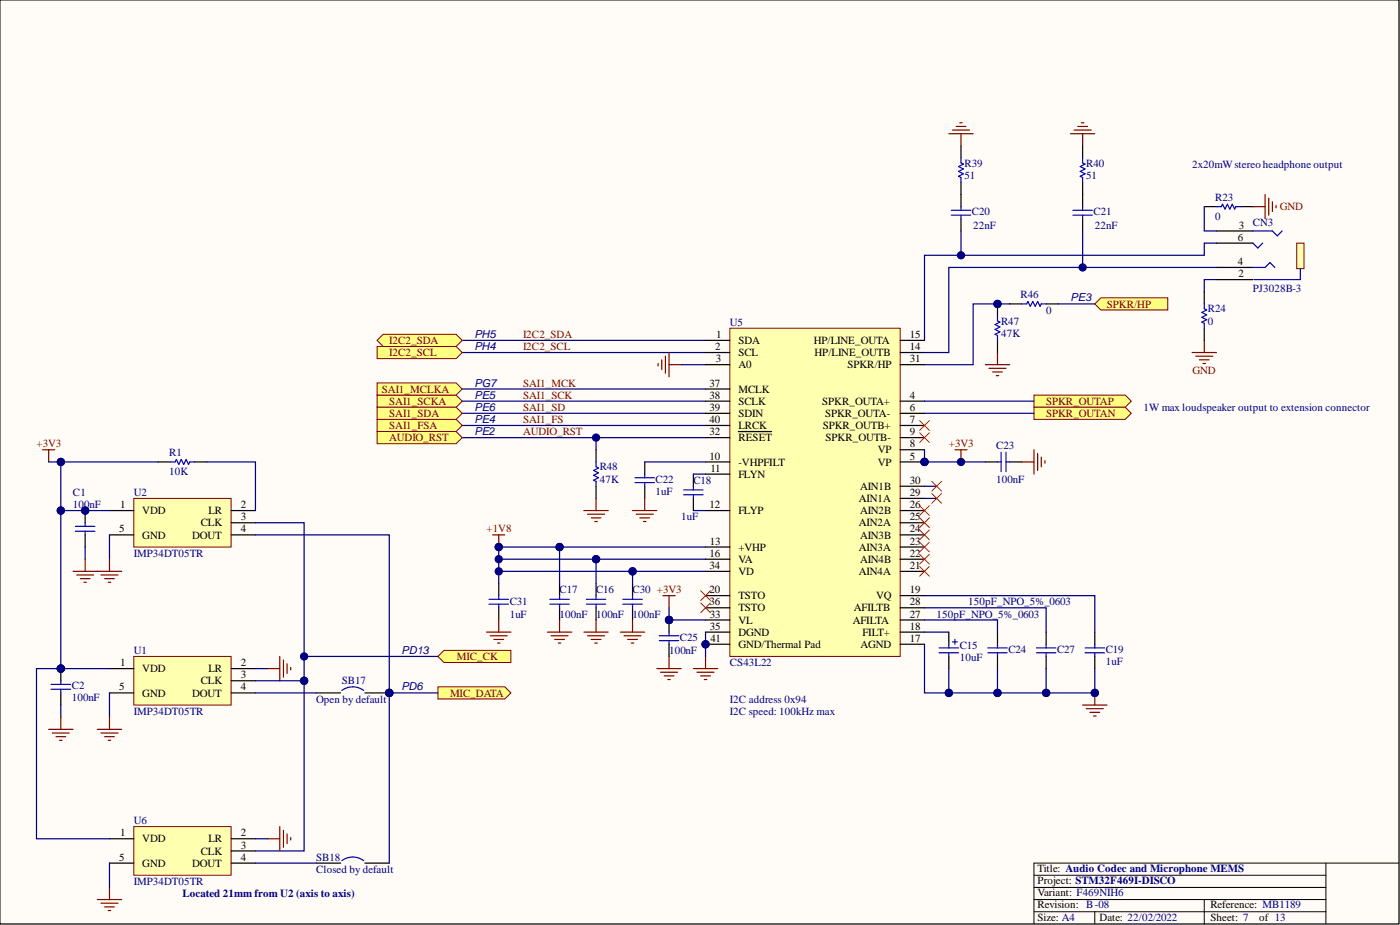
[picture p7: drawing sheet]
<svg xmlns="http://www.w3.org/2000/svg" width="292mm" height="193mm" viewBox="0 0 292 193" stroke-linecap="round" stroke-linejoin="round" font-family="sans-serif">
<defs><g id="words">
<g font-size="2.3" fill="#000080">
<text x="201.3" y="34.7">R39</text>
<text x="226.6" y="34.7">R40</text>
<text x="248.7" y="35">2x20mWstereo headphone output</text>
<text x="201.3" y="37.3">51</text>
<text x="226.6" y="37.3">51</text>
<text x="253.5" y="41.8">R23</text>
<text x="202.8" y="44.9">C20</text>
<text x="203" y="47.7">22nF</text>
<text x="228.2" y="44.9">C21</text>
<text x="228.4" y="47.7">22nF</text>
<text x="253.5" y="45.9">0</text>
<text x="261.4" y="47.2">CN3</text>
<text x="212.9" y="62.1">R46</text>
<text x="218.3" y="65.4">0</text>
<text x="223.3" y="62.9">PE3</text>
<text x="252" y="65.2">R24</text>
<text x="261.4" y="60.9">PJ3028B-3</text>
<text x="99" y="70.5">PH5</text>
<text x="152.3" y="68">U5</text>
<text x="208.9" y="67.7">R47</text>
<text x="208.9" y="70.2">47K</text>
<text x="252" y="67.7">0</text>
<text x="99" y="73">PH4</text>
<text x="99" y="83.2">PE5</text>
<text x="99" y="80.6">PG7</text>
<text x="99" y="85.7">PE6</text>
<text x="99" y="88.3">PE4</text>
<text x="238.6" y="85.7">1W max loudspeaker output to extension connector</text>
<text x="35.3" y="95.1">R1</text>
<text x="99" y="90.8">PE2</text>
<text x="207.9" y="93.6">C23</text>
<text x="35.3" y="99.2">10K</text>
<text x="125.1" y="98.1">R48</text>
<text x="125.1" y="100.7">47K</text>
<text x="136.8" y="100.7">C22</text>
<text x="144.7" y="100.9">C18</text>
<text x="207.9" y="100.7">100nF</text>
<text x="15.2" y="103.5">C1</text>
<text x="15.2" y="106">100nF</text>
<text x="27.9" y="103.5">U2</text>
<text x="136.8" y="103.2">1uF</text>
<text x="142.1" y="108.5">1uF</text>
<text x="27.9" y="116.1">IMP34DT05TR</text>
<text x="116.7" y="123.8">C17</text>
<text x="124.4" y="123.8">C16</text>
<text x="132" y="123.8">C30 +3V3</text>
<text x="106.3" y="126.3">C31</text>
<text x="106.3" y="128.8">1uF</text>
<text x="116.7" y="128.8">100nF</text>
<text x="124.4" y="128.8">100nF</text>
<text x="132" y="128.8">100nF</text>
<text x="195.4" y="128.8">150pF_NPO_5%_0603</text>
<text x="202" y="126.3">150pF_NPO_5%_0603</text>
<text x="27.9" y="136.4">U1</text>
<text x="83.8" y="136.4">PD13</text>
<text x="139.6" y="136.4">100nF</text>
<text x="141.9" y="133.6">C25</text>
<text x="200.2" y="135.4">C15</text>
<text x="200.2" y="138">10uF</text>
<text x="210.4" y="136.2">C24</text>
<text x="220.6" y="136.2">C27</text>
<text x="230.7" y="136.2">C19</text>
<text x="15" y="143.8">C2</text>
<text x="71.3" y="142.8">SB17</text>
<text x="152.3" y="139">CS43L22</text>
<text x="230.7" y="138.7">1uF</text>
<text x="15" y="146.3">100nF</text>
<text x="27.9" y="149.1">IMP34DT05TR</text>
<text x="66" y="146.6">Open by default</text>
<text x="83.8" y="144">PD6</text>
<text x="152.3" y="146.6">I2C address 0x94</text>
<text x="152.3" y="149.1">I2C speed: 100kHz max</text>
<text x="27.9" y="171.9">U6</text>
<text x="66" y="179.5">SB18</text>
<text x="27.9" y="184.6">IMP34DT05TR</text>
<text x="66" y="182.1">Closed by default</text>
<text x="38.1" y="187.2">Located 21mm from U2 (axis to axis)</text>
</g>
<g font-size="2.3">
<text x="258.5" y="47.7">3</text>
<text x="258.3" y="50.2">6</text>
<text x="258.3" y="55.3">4</text>
<text x="258.4" y="57.8">2</text>
<text x="149.4" y="70.5">1</text>
<text x="154.1" y="71.8">SDA</text>
<text x="169.8" y="71.8">HP/LINE_OUTA</text>
<text x="189.8" y="70.5">15</text>
<text x="149.2" y="73">2</text>
<text x="149.3" y="75.6">3</text>
<text x="154.1" y="74.3">SCL</text>
<text x="154.1" y="76.8">A0</text>
<text x="170" y="74.3">HP/LINE_OUTB</text>
<text x="176.8" y="76.8">SPKR/HP</text>
<text x="189.8" y="73">14</text>
<text x="189.8" y="75.6">31</text>
<text x="148.1" y="80.6">37</text>
<text x="148.1" y="83.2">38</text>
<text x="154.1" y="81.9">MCLK</text>
<text x="189.8" y="83.2">4</text>
<text x="148.1" y="85.7">39</text>
<text x="148.1" y="88.3">40</text>
<text x="154.1" y="84.4">SCLK</text>
<text x="154.1" y="87">SDIN</text>
<text x="154.1" y="89.5">LRCK</text>
<text x="171.6" y="84.4">SPKR_OUTA+</text>
<text x="171.7" y="89.5">SPKR_OUTB+</text>
<text x="172.2" y="87">SPKR_OUTA-</text>
<text x="189.8" y="85.7">6</text>
<text x="189.8" y="88.3">7</text>
<text x="148.1" y="95.9">10</text>
<text x="148.1" y="90.8">32</text>
<text x="154.1" y="92.1">RESET</text>
<text x="172.2" y="92.1">SPKR_OUTB-</text>
<text x="183.2" y="94.6">VP</text>
<text x="189.8" y="95.9">5</text>
<text x="189.8" y="93.3">8</text>
<text x="189.8" y="90.8">9</text>
<text x="148.2" y="98.4">11</text>
<text x="154.1" y="97.1">-VHPFILT</text>
<text x="154.1" y="99.7">FLYN</text>
<text x="183.2" y="97.1">VP</text>
<text x="189.8" y="100.9">30</text>
<text x="25" y="106">1</text>
<text x="29.7" y="107.3">VDD</text>
<text x="43.5" y="107.3">LR</text>
<text x="50.3" y="106">2</text>
<text x="148.1" y="106">12</text>
<text x="154.1" y="107.3">FLYP</text>
<text x="179.2" y="104.7">AIN1A</text>
<text x="179.4" y="107.3">AIN2B</text>
<text x="179.4" y="102.2">AIN1B</text>
<text x="189.8" y="106">26</text>
<text x="189.8" y="103.5">29</text>
<text x="24.9" y="111.1">5</text>
<text x="29.7" y="112.3">GND</text>
<text x="40.1" y="112.3">DOUT</text>
<text x="41.9" y="109.8">CLK</text>
<text x="50.3" y="111.1">4</text>
<text x="50.3" y="108.5">3</text>
<text x="148.1" y="113.6">13</text>
<text x="179.2" y="109.8">AIN2A</text>
<text x="179.4" y="112.3">AIN3B</text>
<text x="189.8" y="113.6">23</text>
<text x="189.8" y="111.1">24</text>
<text x="189.8" y="108.5">25</text>
<text x="148.1" y="116.1">16</text>
<text x="148.1" y="118.7">34</text>
<text x="154.1" y="114.9">+VHP</text>
<text x="154.1" y="117.4">VA</text>
<text x="154.1" y="120">VD</text>
<text x="179.2" y="120">AIN4A</text>
<text x="179.2" y="114.9">AIN3A</text>
<text x="179.4" y="117.4">AIN4B</text>
<text x="189.8" y="118.7">21</text>
<text x="189.8" y="116.1">22</text>
<text x="148.1" y="123.8">20</text>
<text x="154.1" y="125">TSTO</text>
<text x="182.8" y="125">VQ</text>
<text x="189.8" y="123.8">19</text>
<text x="148.1" y="126.3">36</text>
<text x="148.1" y="128.8">33</text>
<text x="148.1" y="131.4">35</text>
<text x="154.1" y="130.1">VL</text>
<text x="154.1" y="127.6">TSTO</text>
<text x="177.9" y="130.1">AFILTA</text>
<text x="178.2" y="127.6">AFILTB</text>
<text x="189.8" y="131.4">18</text>
<text x="189.8" y="128.8">27</text>
<text x="189.8" y="126.3">28</text>
<text x="148.2" y="133.9">41</text>
<text x="154.1" y="132.6">DGND</text>
<text x="154.1" y="135.2">GND/Thermal Pad</text>
<text x="179.5" y="135.2">AGND</text>
<text x="179.9" y="132.6">FILT+</text>
<text x="189.8" y="133.9">17</text>
<text x="25" y="139">1</text>
<text x="29.7" y="140.2">VDD</text>
<text x="41.9" y="142.8">CLK</text>
<text x="43.5" y="140.2">LR</text>
<text x="50.3" y="141.5">3</text>
<text x="50.3" y="139">2</text>
<text x="24.9" y="144">5</text>
<text x="29.7" y="145.3">GND</text>
<text x="40.1" y="145.3">DOUT</text>
<text x="50.3" y="144">4</text>
<text x="24.9" y="179.5">5</text>
<text x="25" y="174.5">1</text>
<text x="29.7" y="175.7">VDD</text>
<text x="41.9" y="178.3">CLK</text>
<text x="43.5" y="175.7">LR</text>
<text x="50.3" y="179.5">4</text>
<text x="50.3" y="177">3</text>
<text x="50.3" y="174.5">2</text>
<text x="29.7" y="180.8">GND</text>
<text x="40.1" y="180.8">DOUT</text>
<text x="216.5" y="181.8">Title: Audio Codec and Microphone MEMS</text>
<text x="216.5" y="184.4">Project: STM32F469I-DISCO</text>
<text x="216.5" y="189.4">Revision: B-08</text>
<text x="216.5" y="186.9">Variant: F469NIH6</text>
<text x="252.5" y="189.4">Reference: MB1189</text>
<text x="216.5" y="192.2">Size: A4</text>
<text x="229.4" y="192.2">Date: 22/02/2022</text>
<text x="252.5" y="192.2">Sheet: 7</text>
<text x="262.7" y="192.2">of 13</text>
</g>
<g font-size="2.3" fill="#800000">
<text x="267" y="43.9">GND</text>
<text x="231" y="64.2">SPKR/HP</text>
<text x="81.2" y="71.8">I2C2_SDA</text>
<text x="109.1" y="70.5">I2C2_SDA</text>
<text x="81.2" y="74.3">I2C2_SCL</text>
<text x="109.1" y="73">I2C2_SCL</text>
<text x="79.7" y="81.9">SAI1_MCLKA</text>
<text x="109.1" y="80.6">SAI1_MCK</text>
<text x="109.1" y="83.2">SAI1_SCK</text>
<text x="248.8" y="78.1">GND</text>
<text x="81.2" y="84.4">SAI1_SCKA</text>
<text x="81.2" y="89.5">SAI1_FSA</text>
<text x="81.2" y="87">SAI1_SDA</text>
<text x="109.1" y="85.7">SAI1_SD</text>
<text x="109.1" y="88.3">SAI1_FS</text>
<text x="218.3" y="84.4">SPKR_OUTAP</text>
<text x="218.3" y="87">SPKR_OUTAN</text>
<text x="7.6" y="93.3">+3V3</text>
<text x="81.2" y="92.1">AUDIO_RST</text>
<text x="109.1" y="90.8">AUDIO_RST</text>
<text x="198" y="93.3">+3V3</text>
<text x="101.5" y="111.1">+1V8</text>
<text x="95.3" y="137.7">MIC_CK</text>
<text x="93.9" y="145.3">MIC_DATA</text>
</g>
</g></defs>
<path d="M0 0h291.9v192.7h-291.9z" fill-rule="evenodd" fill="#fffcf8"/>
<path d="M0 0h291.9v192.7h-291.9z" fill="none" stroke="#000" stroke-width=".21"/>
<path d="M0 0h291.9v192.7h-291.9z" fill-rule="evenodd" fill="#fffcf8"/>
<path d="M0 0h291.9v192.7h-291.9zM215.7 182.6h60.9M215.7 185.1h60.9M215.7 190.2h60.9M215.7 187.7h60.9M228.4 190.2v2.5M251.3 187.7v5M276.6 180.1v12.6M291.9 180.1h-76.2v12.6" fill="none" stroke="#000" stroke-width=".21"/>
<g fill="none" stroke="#800000" stroke-width=".25">
<path d="M198 27.9h5M198.7 27.1h3.6M199.5 26.4h2M200.2 25.6h.6M200.5 27.9v2.5M223.3 27.9h5.1M224.1 27.1h3.6M224.9 26.4h2M225.6 25.6h.5M225.9 27.9v2.5M121.8 106.5h5.1M122.6 107.3h3.5"/>
<path d="M123.3 108h2.1M124.1 108.8h.5M124.4 104v2.5M144.7 139.5h5M147.2 136.9v2.6M145.4 140.2h3.6M146.2 141h2M147 141.8h.5"/>
</g>
<path d="M225.9 48.2v7.6M96.4 73.5h50.8M96.4 71h50.8M96.4 83.7h50.8M96.4 86.2h50.8M96.4 88.8h50.8M96.4 81.2h50.8M147.2 131.9v5" fill="none" stroke="#000080" stroke-width=".25"/>
<circle cx="225.9" cy="55.8" r=".76" fill="#000080"/>
<circle cx="225.9" cy="55.8" r=".76" fill="none" stroke="#000080" stroke-width=".21"/>
<path d="M200.5 48.2v5.1" fill="none" stroke="#000080" stroke-width=".25"/>
<circle cx="200.5" cy="53.3" r=".76" fill="#000080"/>
<circle cx="200.5" cy="53.3" r=".76" fill="none" stroke="#000080" stroke-width=".21"/>
<path d="M137.3 75.8v.5M138.1 75.1v2M138.8 74.3v3.6M139.6 73.5v5.1M139.6 76.1h2.5" fill="none" stroke="#800000" stroke-width=".25"/>
<path d="M142.1 76.1h5.1M96.4 91.3h50.8" fill="none" stroke="#000080" stroke-width=".25"/>
<circle cx="192.9" cy="96.4" r=".76" fill="#000080"/>
<circle cx="192.9" cy="96.4" r=".76" fill="none" stroke="#000080" stroke-width=".21"/>
<circle cx="147.2" cy="134.4" r=".76" fill="#000080"/>
<circle cx="147.2" cy="134.4" r=".76" fill="none" stroke="#000080" stroke-width=".21"/>
<path d="M152.3 68.5h35.5v68.4h-35.5z" fill-rule="evenodd" fill="#ffffb0"/>
<path d="M152.3 68.5h35.5v68.4h-35.5z" fill="none" stroke="#800000" stroke-width=".21"/>
<path d="M147.2 71h5.1M147.2 73.5h5.1M147.2 76.1h5.1M187.8 83.7h5.1M187.8 96.4h5.1" fill="none" stroke="#000" stroke-width=".25"/>
<circle cx="192.9" cy="96.4" r=".76" fill="#000080"/>
<circle cx="192.9" cy="96.4" r=".76" fill="none" stroke="#000080" stroke-width=".21"/>
<g fill="none" stroke="#000" stroke-width=".25">
<path d="M187.8 73.5h5.1M187.8 71h5.1M187.8 76.1h5.1M147.2 86.2h5.1M147.2 88.8h5.1M147.2 91.3h5.1M147.2 96.4h5.1M147.2 98.9h5.1M147.2 81.2h5.1M147.2 83.7h5.1M154.1 90h6.9M187.8 86.2h5.1"/>
<path d="M187.8 88.8h5.1M187.8 93.8h5.1M187.8 91.3h5.1M147.2 106.5h5.1M147.2 114.1h5.1M147.2 116.7h5.1M147.2 119.2h5.1M187.8 106.5h5.1M187.8 114.1h5.1M187.8 116.7h5.1M187.8 119.2h5.1M187.8 111.6h5.1"/>
<path d="M187.8 109h5.1M187.8 104h5.1M187.8 101.4h5.1M147.2 134.4h5.1M147.2 131.9h5.1M147.2 124.3h5.1M147.2 129.3h5.1M147.2 126.8h5.1M187.8 134.4h5.1M187.8 131.9h5.1M187.8 124.3h5.1M187.8 129.3h5.1"/>
<path d="M187.8 126.8h5.1"/>
</g>
<circle cx="147.2" cy="134.4" r=".76" fill="#000080"/>
<circle cx="147.2" cy="134.4" r=".76" fill="none" stroke="#000080" stroke-width=".21"/>
<g fill="none" stroke="#f00" stroke-width=".21">
<path d="M191.9 87.7l2 2.1M191.9 90.3l2 2M193.9 87.7l-2 2.1M193.9 90.3l-2 2M191.9 105.5l2 2M191.9 108l2 2.1M191.9 110.6l2 2M191.9 113.1l2 2M191.9 115.6l2 2.1M193.9 105.5l-2 2M193.9 108l-2 2.1M193.9 110.6l-2 2"/>
<path d="M193.9 113.1l-2 2M193.9 115.6l-2 2.1M146.2 125.8l2 2M146.2 123.2l2 2.1M148.2 125.8l-2 2M148.2 123.2l-2 2.1"/>
</g>
<path d="M124.4 91.3v2.5" fill="none" stroke="#000080" stroke-width=".25"/>
<circle cx="124.4" cy="91.3" r=".76" fill="#000080"/>
<circle cx="124.4" cy="91.3" r=".76" fill="none" stroke="#000080" stroke-width=".21"/>
<path d="M200.5 30.4v2.6M200.5 38v5.1M225.9 30.4v2.6M225.9 38v5.1M200.5 45.6v2.6M225.9 45.6v2.6M33 96.4h2.5M40.6 96.4h2.5M208.1 131.9v2.5M208.1 136.9v2.6M218.3 131.9v2.5M218.3 136.9v2.6" fill="none" stroke="#000" stroke-width=".25"/>
<g fill="none" stroke="#00f" stroke-width=".25">
<path d="M200.5 33v1l.5 .2-1 .5 1 .6-1 .5 1 .5-1 .5 .5 .2v1M225.9 33v1l.5 .2-1 .5 1 .6-1 .5 1 .5-1 .5 .5 .2v1M198.5 43.9h4M198.5 44.9h4M200.5 43.1v.8M200.5 44.9v.7M223.9 43.9h4M223.9 44.9h4M225.9 43.1v.8M225.9 44.9v.7M35.5 96.4h1l.3-.5 .5 1 .5-1 .5 1 .5-1 .5 1 .3-.5h1M206.1 135.2h4"/>
<path d="M206.1 136.2h4M208.1 134.4v.8M208.1 136.2v.7M216.2 135.2h4.1M216.2 136.2h4.1M218.3 134.4v.8M218.3 136.2v.7"/>
</g>
<path d="M205.6 76.1h5.1M206.3 76.8h3.6M207.1 77.6h2M207.9 78.4h.5M208.1 73.5v2.6M213.2 96.4h2.5M215.7 93.8v5.1M216.5 94.6v3.5M217.3 95.4v2M218 96.1v.5" fill="none" stroke="#800000" stroke-width=".25"/>
<path d="M191.9 118.2l2 2M193.9 118.2l-2 2" fill="none" stroke="#f00" stroke-width=".21"/>
<path d="M78.7 82.4h16.5l1.2 1.3-1.2 1.3h-16.5z" fill-rule="evenodd" fill="#ffff80"/>
<path d="M78.7 82.4h16.5l1.2 1.3-1.2 1.3h-16.5z" fill="none" stroke="#800000" stroke-width=".21"/>
<path d="M78.7 87.5h16.5l1.2 1.3-1.2 1.2h-16.5z" fill-rule="evenodd" fill="#ffff80"/>
<path d="M78.7 87.5h16.5l1.2 1.3-1.2 1.2h-16.5z" fill="none" stroke="#800000" stroke-width=".21"/>
<path d="M78.7 85h16.5l1.2 1.2-1.2 1.3h-16.5z" fill-rule="evenodd" fill="#ffff80"/>
<path d="M78.7 85h16.5l1.2 1.2-1.2 1.3h-16.5z" fill="none" stroke="#800000" stroke-width=".21"/>
<path d="M78.7 90h16.5l1.2 1.3-1.2 1.3h-16.5z" fill-rule="evenodd" fill="#ffff80"/>
<path d="M78.7 90h16.5l1.2 1.3-1.2 1.3h-16.5z" fill="none" stroke="#800000" stroke-width=".21"/>
<path d="M78.7 79.9h16.5l1.2 1.3-1.2 1.2h-16.5z" fill-rule="evenodd" fill="#ffff80"/>
<path d="M78.7 79.9h16.5l1.2 1.3-1.2 1.2h-16.5z" fill="none" stroke="#800000" stroke-width=".21"/>
<path d="M144.7 98.9v2.5M144.7 104v2.5M104.1 121.7v2.6M104.1 126.8v2.5" fill="none" stroke="#000" stroke-width=".25"/>
<path d="M142.6 103.2h4.1M142.6 102.2h4.1M144.7 101.4v.8M144.7 103.2v.8M102 126h4.1M102 125h4.1M104.1 124.3v.7M104.1 126v.8" fill="none" stroke="#00f" stroke-width=".25"/>
<path d="M101.5 131.9h5.1M102.3 132.6h3.5M103 133.4h2.1M103.8 134.2h.5M104.1 129.3v2.6M137.1 139.5h5M139.6 136.9v2.6M137.8 140.2h3.6M138.6 141h2M139.3 141.8h.5" fill="none" stroke="#800000" stroke-width=".25"/>
<circle cx="139.6" cy="129.3" r=".76" fill="#000080"/>
<circle cx="139.6" cy="129.3" r=".76" fill="none" stroke="#000080" stroke-width=".21"/>
<path d="M139.6 129.3v2.6" fill="none" stroke="#000" stroke-width=".25"/>
<circle cx="139.6" cy="129.3" r=".76" fill="#000080"/>
<circle cx="139.6" cy="129.3" r=".76" fill="none" stroke="#000080" stroke-width=".21"/>
<path d="M116.7 121.7v2.6M116.7 126.8v2.5M124.4 121.7v2.6M124.4 126.8v2.5M132 121.7v2.6M132 126.8v2.5M139.6 134.4v2.5" fill="none" stroke="#000" stroke-width=".25"/>
<g fill="none" stroke="#00f" stroke-width=".25">
<path d="M114.7 126h4.1M114.7 125h4.1M116.7 124.3v.7M116.7 126v.8M122.3 126h4.1M122.3 125h4.1M124.4 124.3v.7M124.4 126v.8M129.9 126h4.1M129.9 125h4.1M132 124.3v.7M132 126v.8"/>
<path d="M137.6 133.6h4M137.6 132.6h4M139.6 131.9v.7M139.6 133.6v.8"/>
</g>
<g fill="none" stroke="#800000" stroke-width=".25">
<path d="M114.2 131.9h5.1M115 132.6h3.5M115.7 133.4h2.1M116.5 134.2h.5M116.7 129.3v2.6M121.8 131.9h5.1M122.6 132.6h3.5M123.3 133.4h2.1M124.1 134.2h.5M124.4 129.3v2.6M129.4 131.9h5.1M130.2 132.6h3.6"/>
<path d="M131 133.4h2M131.7 134.2h.5M132 129.3v2.6"/>
</g>
<path d="M147.2 116.7h-22.8v5" fill="none" stroke="#000080" stroke-width=".25"/>
<circle cx="124.4" cy="116.7" r=".76" fill="#000080"/>
<circle cx="124.4" cy="116.7" r=".76" fill="none" stroke="#000080" stroke-width=".21"/>
<path d="M147.2 114.1h-30.5v7.6" fill="none" stroke="#000080" stroke-width=".25"/>
<circle cx="116.7" cy="114.1" r=".76" fill="#000080"/>
<circle cx="116.7" cy="114.1" r=".76" fill="none" stroke="#000080" stroke-width=".21"/>
<path d="M147.2 119.2h-15.2v2.5" fill="none" stroke="#000080" stroke-width=".25"/>
<circle cx="132" cy="119.2" r=".76" fill="#000080"/>
<circle cx="132" cy="119.2" r=".76" fill="none" stroke="#000080" stroke-width=".21"/>
<path d="M116.7 114.1h-12.6v7.6" fill="none" stroke="#000080" stroke-width=".25"/>
<circle cx="116.7" cy="114.1" r=".76" fill="#000080"/>
<circle cx="116.7" cy="114.1" r=".76" fill="none" stroke="#000080" stroke-width=".21"/>
<circle cx="104.1" cy="114.1" r=".76" fill="#000080"/>
<circle cx="104.1" cy="114.1" r=".76" fill="none" stroke="#000080" stroke-width=".21"/>
<path d="M104.1 116.7h20.3" fill="none" stroke="#000080" stroke-width=".25"/>
<circle cx="124.4" cy="116.7" r=".76" fill="#000080"/>
<circle cx="124.4" cy="116.7" r=".76" fill="none" stroke="#000080" stroke-width=".21"/>
<circle cx="104.1" cy="116.7" r=".76" fill="#000080"/>
<circle cx="104.1" cy="116.7" r=".76" fill="none" stroke="#000080" stroke-width=".21"/>
<path d="M104.1 119.2h27.9" fill="none" stroke="#000080" stroke-width=".25"/>
<circle cx="132" cy="119.2" r=".76" fill="#000080"/>
<circle cx="132" cy="119.2" r=".76" fill="none" stroke="#000080" stroke-width=".21"/>
<circle cx="104.1" cy="119.2" r=".76" fill="#000080"/>
<circle cx="104.1" cy="119.2" r=".76" fill="none" stroke="#000080" stroke-width=".21"/>
<path d="M144.7 98.9h2.5M144.7 106.5h2.5M139.6 126.8v2.5h7.6" fill="none" stroke="#000080" stroke-width=".25"/>
<path d="M138.3 124.3h2.6M139.6 124.3v2.5" fill="none" stroke="#800000" stroke-width=".25"/>
<circle cx="139.6" cy="129.3" r=".76" fill="#000080"/>
<circle cx="139.6" cy="129.3" r=".76" fill="none" stroke="#000080" stroke-width=".21"/>
<path d="M124.4 93.8v2.6M134.5 96.4v2.5M124.4 101.4v2.6M134.5 101.4v2.6M198 131.9v2.5M198 136.9v2.6M228.4 131.9v2.5M228.4 136.9v2.6" fill="none" stroke="#000" stroke-width=".25"/>
<g fill="none" stroke="#00f" stroke-width=".25">
<path d="M124.4 96.4v1l.5 .2-1 .5 1 .6-1 .5 1 .5-1 .5 .5 .2v1M132.5 99.7h4M134.5 98.9v.8M132.5 100.7h4M134.5 100.7v.7M195.9 135.2h4.1M195.9 136.2h4.1M198 134.4v.8M198 136.2v.7M198.7 133.9h1M199.2 133.4v1M226.4 135.2h4.1"/>
<path d="M226.4 136.2h4.1M228.4 134.4v.8M228.4 136.2v.7"/>
</g>
<path d="M132 106.5h5.1M132.7 107.3h3.6M133.5 108h2M134.3 108.8h.5M134.5 104v2.5" fill="none" stroke="#800000" stroke-width=".25"/>
<path d="M134.5 96.4h12.7M192.9 124.3h35.5v7.6M192.9 126.8h25.4v5.1M192.9 129.3h15.2v2.6M192.9 131.9h5.1M218.3 139.5v5.1h10.1v-5.1" fill="none" stroke="#000080" stroke-width=".25"/>
<circle cx="228.4" cy="144.6" r=".76" fill="#000080"/>
<circle cx="228.4" cy="144.6" r=".76" fill="none" stroke="#000080" stroke-width=".21"/>
<circle cx="218.3" cy="144.6" r=".76" fill="#000080"/>
<circle cx="218.3" cy="144.6" r=".76" fill="none" stroke="#000080" stroke-width=".21"/>
<path d="M208.1 139.5v5.1h10.2" fill="none" stroke="#000080" stroke-width=".25"/>
<circle cx="218.3" cy="144.6" r=".76" fill="#000080"/>
<circle cx="218.3" cy="144.6" r=".76" fill="none" stroke="#000080" stroke-width=".21"/>
<circle cx="208.1" cy="144.6" r=".76" fill="#000080"/>
<circle cx="208.1" cy="144.6" r=".76" fill="none" stroke="#000080" stroke-width=".21"/>
<path d="M198 139.5v5.1h10.1" fill="none" stroke="#000080" stroke-width=".25"/>
<circle cx="208.1" cy="144.6" r=".76" fill="#000080"/>
<circle cx="208.1" cy="144.6" r=".76" fill="none" stroke="#000080" stroke-width=".21"/>
<circle cx="198" cy="144.6" r=".76" fill="#000080"/>
<circle cx="198" cy="144.6" r=".76" fill="none" stroke="#000080" stroke-width=".21"/>
<path d="M192.9 134.4v10.2h5.1" fill="none" stroke="#000080" stroke-width=".25"/>
<circle cx="198" cy="144.6" r=".76" fill="#000080"/>
<circle cx="198" cy="144.6" r=".76" fill="none" stroke="#000080" stroke-width=".21"/>
<path d="M225.9 147.1h5.1M226.6 147.8h3.6M227.4 148.6h2M228.2 149.4h.5M228.4 144.6v2.5" fill="none" stroke="#800000" stroke-width=".25"/>
<circle cx="228.4" cy="144.6" r=".76" fill="#000080"/>
<circle cx="228.4" cy="144.6" r=".76" fill="none" stroke="#000080" stroke-width=".21"/>
<path d="M199.2 93.8h2.6M200.5 93.8v2.6" fill="none" stroke="#800000" stroke-width=".25"/>
<circle cx="200.5" cy="96.4" r=".76" fill="#000080"/>
<circle cx="200.5" cy="96.4" r=".76" fill="none" stroke="#000080" stroke-width=".21"/>
<path d="M205.6 96.4h2.5M210.7 96.4h2.5" fill="none" stroke="#000" stroke-width=".25"/>
<path d="M208.1 96.4h.8M208.9 94.3v4.1M209.9 94.3v4.1M209.9 96.4h.8" fill="none" stroke="#00f" stroke-width=".25"/>
<path d="M78.7 72.3h16.5l1.2 1.2-1.2 1.3h-16.5z" fill-rule="evenodd" fill="#ffff80"/>
<path d="M78.7 72.3h16.5l1.2 1.2-1.2 1.3h-16.5z" fill="none" stroke="#800000" stroke-width=".21"/>
<path d="M78.7 71l1.2-1.3h15.3l1.2 1.3-1.2 1.3h-15.3z" fill-rule="evenodd" fill="#ffff80"/>
<path d="M78.7 71l1.2-1.3h15.3l1.2 1.3-1.2 1.3h-15.3z" fill="none" stroke="#800000" stroke-width=".21"/>
<path d="M102.8 111.6h2.5M104.1 111.6v2.5" fill="none" stroke="#800000" stroke-width=".25"/>
<circle cx="104.1" cy="114.1" r=".76" fill="#000080"/>
<circle cx="104.1" cy="114.1" r=".76" fill="none" stroke="#000080" stroke-width=".21"/>
<path d="M91.4 136.9l1.2-1.2h14v2.5h-14z" fill-rule="evenodd" fill="#ffff80"/>
<path d="M91.4 136.9l1.2-1.2h14v2.5h-14z" fill="none" stroke="#800000" stroke-width=".21"/>
<path d="M91.4 143.3h13.9l1.3 1.3-1.3 1.2h-13.9z" fill-rule="evenodd" fill="#ffff80"/>
<path d="M91.4 143.3h13.9l1.3 1.3-1.3 1.2h-13.9z" fill="none" stroke="#800000" stroke-width=".21"/>
<path d="M215.7 82.4h19.1l1.2 1.3-1.2 1.3h-19.1z" fill-rule="evenodd" fill="#ffff80"/>
<path d="M215.7 82.4h19.1l1.2 1.3-1.2 1.3h-19.1z" fill="none" stroke="#800000" stroke-width=".21"/>
<path d="M215.7 85h19.1l1.2 1.2-1.2 1.3h-19.1z" fill-rule="evenodd" fill="#ffff80"/>
<path d="M215.7 85h19.1l1.2 1.2-1.2 1.3h-19.1z" fill="none" stroke="#800000" stroke-width=".21"/>
<path d="M228.4 63.4l1.3-1.3h13.9v2.6h-13.9z" fill-rule="evenodd" fill="#ffff80"/>
<path d="M228.4 63.4l1.3-1.3h13.9v2.6h-13.9z" fill="none" stroke="#800000" stroke-width=".21"/>
<circle cx="208.1" cy="63.4" r=".76" fill="#000080"/>
<circle cx="208.1" cy="63.4" r=".76" fill="none" stroke="#000080" stroke-width=".21"/>
<path d="M208.1 63.4v2.5M208.1 71v2.5" fill="none" stroke="#000" stroke-width=".25"/>
<circle cx="208.1" cy="63.4" r=".76" fill="#000080"/>
<circle cx="208.1" cy="63.4" r=".76" fill="none" stroke="#000080" stroke-width=".21"/>
<path d="M208.1 65.9v1.1l.5 .2-1 .5 1 .5-1 .5 1 .5-1 .5 .5 .3v1" fill="none" stroke="#00f" stroke-width=".25"/>
<path d="M253.8 55.8h-55.8v17.7h-5.1M210.7 63.4h-7.7v12.7h-10.1M192.9 93.8v2.6h12.7M192.9 86.2h22.8M192.9 83.7h22.8M192.9 104h2.5M192.9 101.4h2.5" fill="none" stroke="#000080" stroke-width=".25"/>
<circle cx="192.9" cy="96.4" r=".76" fill="#000080"/>
<circle cx="192.9" cy="96.4" r=".76" fill="none" stroke="#000080" stroke-width=".21"/>
<path d="M210.7 63.4h2.5M218.3 63.4h2.5" fill="none" stroke="#000" stroke-width=".25"/>
<path d="M213.2 63.4h1l.3-.5 .5 1 .5-1 .5 1 .5-1 .5 1 .3-.5h1" fill="none" stroke="#00f" stroke-width=".25"/>
<path d="M220.8 63.4h7.6" fill="none" stroke="#000080" stroke-width=".25"/>
<path d="M8.9 93.8h2.5M10.2 93.8v2.6" fill="none" stroke="#800000" stroke-width=".25"/>
<circle cx="17.8" cy="106.5" r=".76" fill="#000080"/>
<circle cx="17.8" cy="106.5" r=".76" fill="none" stroke="#000080" stroke-width=".21"/>
<path d="M17.8 106.5v2.5M17.8 111.6v2.5" fill="none" stroke="#000" stroke-width=".25"/>
<circle cx="17.8" cy="106.5" r=".76" fill="#000080"/>
<circle cx="17.8" cy="106.5" r=".76" fill="none" stroke="#000080" stroke-width=".21"/>
<path d="M15.7 109.8h4.1M15.7 110.8h4.1M17.8 109v.8M17.8 110.8v.8" fill="none" stroke="#00f" stroke-width=".25"/>
<path d="M27.9 104h20.3v10.1h-20.3z" fill-rule="evenodd" fill="#ffffb0"/>
<path d="M27.9 104h20.3v10.1h-20.3z" fill="none" stroke="#800000" stroke-width=".21"/>
<path d="M22.8 111.6h5.1M22.8 106.5h5.1M48.2 111.6h5.1M48.2 109h5.1M48.2 106.5h5.1" fill="none" stroke="#000" stroke-width=".25"/>
<path d="M33 96.4h-20.3v10.1h10.1M43.1 96.4h10.2v10.1" fill="none" stroke="#000080" stroke-width=".25"/>
<circle cx="12.7" cy="106.5" r=".76" fill="#000080"/>
<circle cx="12.7" cy="106.5" r=".76" fill="none" stroke="#000080" stroke-width=".21"/>
<circle cx="12.7" cy="96.4" r=".76" fill="#000080"/>
<circle cx="12.7" cy="96.4" r=".76" fill="none" stroke="#000080" stroke-width=".21"/>
<path d="M17.8 114.1v2.6M22.8 111.6v5.1" fill="none" stroke="#000080" stroke-width=".25"/>
<path d="M15.2 119.2h10.2M16 120h3.5M17.8 116.7v2.5M21.1 120h3.5M22.8 116.7v2.5M16.8 120.7h2M17.5 121.5h.5M21.8 120.7h2.1M22.6 121.5h.5" fill="none" stroke="#800000" stroke-width=".25"/>
<circle cx="12.7" cy="139.5" r=".76" fill="#000080"/>
<circle cx="12.7" cy="139.5" r=".76" fill="none" stroke="#000080" stroke-width=".21"/>
<path d="M12.7 139.5v2.5M12.7 144.6v2.5" fill="none" stroke="#000" stroke-width=".25"/>
<circle cx="12.7" cy="139.5" r=".76" fill="#000080"/>
<circle cx="12.7" cy="139.5" r=".76" fill="none" stroke="#000080" stroke-width=".21"/>
<path d="M10.7 142.8h4M10.7 143.8h4M12.7 142v.8M12.7 143.8v.8" fill="none" stroke="#00f" stroke-width=".25"/>
<path d="M27.9 136.9h20.3v10.2h-20.3z" fill-rule="evenodd" fill="#ffffb0"/>
<path d="M27.9 136.9h20.3v10.2h-20.3z" fill="none" stroke="#800000" stroke-width=".21"/>
<path d="M22.8 139.5h5.1M48.2 139.5h5.1M22.8 144.6h5.1M48.2 144.6h5.1M48.2 142h5.1" fill="none" stroke="#000" stroke-width=".25"/>
<path d="M12.7 106.5v33h10.1" fill="none" stroke="#000080" stroke-width=".25"/>
<circle cx="12.7" cy="139.5" r=".76" fill="#000080"/>
<circle cx="12.7" cy="139.5" r=".76" fill="none" stroke="#000080" stroke-width=".21"/>
<circle cx="12.7" cy="106.5" r=".76" fill="#000080"/>
<circle cx="12.7" cy="106.5" r=".76" fill="none" stroke="#000080" stroke-width=".21"/>
<path d="M53.3 109h10.2v33h-10.2M53.3 139.5h2.5M12.7 147.1v2.5M22.8 144.6v5" fill="none" stroke="#000080" stroke-width=".25"/>
<g fill="none" stroke="#800000" stroke-width=".25">
<path d="M55.8 139.5h2.6M58.4 136.9v5.1M59.1 137.7v3.6M59.9 138.5v2M60.7 139.2v.5M10.2 152.2h5M10.9 152.9h3.6M11.7 153.7h2M12.4 154.4h.5M12.7 149.6v2.6M20.3 152.2h5.1M21.1 152.9h3.5"/>
<path d="M21.8 153.7h2.1M22.6 154.4h.5M22.8 149.6v2.6"/>
</g>
<circle cx="63.5" cy="142" r=".76" fill="#000080"/>
<circle cx="63.5" cy="142" r=".76" fill="none" stroke="#000080" stroke-width=".21"/>
<path d="M63.5 136.9h27.9" fill="none" stroke="#000080" stroke-width=".25"/>
<circle cx="63.5" cy="136.9" r=".76" fill="#000080"/>
<circle cx="63.5" cy="136.9" r=".76" fill="none" stroke="#000080" stroke-width=".21"/>
<path d="M10.2 96.4h2.5" fill="none" stroke="#000080" stroke-width=".25"/>
<circle cx="12.7" cy="96.4" r=".76" fill="#000080"/>
<circle cx="12.7" cy="96.4" r=".76" fill="none" stroke="#000080" stroke-width=".21"/>
<path d="M248.7 73.5h5.1M249.5 74.3h3.5M250.2 75.1h2.1M251 75.8h.5M251.3 71v2.5" fill="none" stroke="#800000" stroke-width=".25"/>
<path d="M253.8 58.3h-2.5v2.6" fill="none" stroke="#000080" stroke-width=".25"/>
<path d="M253.8 58.3h7.6M253.8 50.7h7.6M253.8 55.8h7.6" fill="none" stroke="#000" stroke-width=".25"/>
<path d="M261.4 55.8h2.6l1-1 1 1" fill="none" stroke="#0000b4" stroke-width=".25"/>
<path d="M270.6 50.7h1.5v5.3h-1.5z" fill-rule="evenodd" fill="#ffffb0"/>
<path d="M270.6 50.7h1.5v5.3h-1.5z" fill="none" stroke="#800000" stroke-width=".21"/>
<path d="M261.4 50.7l1 1 1-1M261.4 48.2h4.1l1 1 1-1M271.3 56v2.3h-9.6" fill="none" stroke="#0000b4" stroke-width=".25"/>
<path d="M251.3 43.1h2.5M253.8 48.2h7.6M258.9 43.1h2.5M251.3 60.9v2.5M251.3 68.5v2.5" fill="none" stroke="#000" stroke-width=".25"/>
<path d="M253.8 43.1h1l.3-.5 .5 1 .5-1 .5 1 .5-1 .5 1 .3-.5h1M251.3 63.4v1l.5 .3-1 .5 1 .5-1 .5 1 .5-1 .5 .5 .3v1" fill="none" stroke="#00f" stroke-width=".25"/>
<path d="M261.4 43.1h2.6M264 40.6v5M264.7 41.3v3.6M265.5 42.1v2M266.2 42.9v.5" fill="none" stroke="#800000" stroke-width=".25"/>
<path d="M251.3 43.1v5.1h2.5M253.8 50.7h-2.5v2.6h-58.4v17.7" fill="none" stroke="#000080" stroke-width=".25"/>
<path d="M194.4 100.4l2 2.1M194.4 103l2 2M196.4 100.4l-2 2.1M196.4 103l-2 2" fill="none" stroke="#f00" stroke-width=".21"/>
<path d="M27.9 172.4h20.3v10.2h-20.3z" fill-rule="evenodd" fill="#ffffb0"/>
<path d="M27.9 172.4h20.3v10.2h-20.3z" fill="none" stroke="#800000" stroke-width=".21"/>
<path d="M22.8 175h5.1M48.2 177.5h5.1M48.2 175h5.1M22.8 180.1h5.1M48.2 180.1h5.1" fill="none" stroke="#000" stroke-width=".25"/>
<path d="M20.3 187.7h5.1M21.1 188.4h3.5M21.8 189.2h2.1M22.6 189.9h.5M22.8 185.1v2.6" fill="none" stroke="#800000" stroke-width=".25"/>
<path d="M12.7 139.5h-5.1v35.5h15.2M22.8 180.1v5" fill="none" stroke="#000080" stroke-width=".25"/>
<circle cx="12.7" cy="139.5" r=".76" fill="#000080"/>
<circle cx="12.7" cy="139.5" r=".76" fill="none" stroke="#000080" stroke-width=".21"/>
<path d="M63.5 142v35.5h-10.2" fill="none" stroke="#000080" stroke-width=".25"/>
<circle cx="63.5" cy="142" r=".76" fill="#000080"/>
<circle cx="63.5" cy="142" r=".76" fill="none" stroke="#000080" stroke-width=".21"/>
<path d="M55.8 175h2.6M58.4 172.4v5.1M59.1 173.2v3.6M59.9 174v2M60.7 174.7v.5" fill="none" stroke="#800000" stroke-width=".25"/>
<path d="M53.3 175h2.5" fill="none" stroke="#000080" stroke-width=".25"/>
<circle cx="81.2" cy="144.6" r=".76" fill="#000080"/>
<circle cx="81.2" cy="144.6" r=".76" fill="none" stroke="#000080" stroke-width=".21"/>
<path d="M66 144.6h5.1M76.1 144.6h5.1" fill="none" stroke="#000" stroke-width=".25"/>
<circle cx="81.2" cy="144.6" r=".76" fill="#000080"/>
<circle cx="81.2" cy="144.6" r=".76" fill="none" stroke="#000080" stroke-width=".21"/>
<path d="M71.3 144a3.8 3.8 0 0 1 4.6 0M71.3 179.5a3.8 3.8 0 0 1 4.6 0" fill="none" stroke="#00f" stroke-width=".25"/>
<path d="M66 180.1h5.1M76.1 180.1h5.1" fill="none" stroke="#000" stroke-width=".25"/>
<path d="M53.3 144.6h12.7M91.4 144.6h-10.2v35.5M53.3 180.1h12.7" fill="none" stroke="#000080" stroke-width=".25"/>
<circle cx="81.2" cy="144.6" r=".76" fill="#000080"/>
<circle cx="81.2" cy="144.6" r=".76" fill="none" stroke="#000080" stroke-width=".21"/>
<path d="M53.3 111.6h27.9v33" fill="none" stroke="#000080" stroke-width=".25"/>
<circle cx="81.2" cy="144.6" r=".76" fill="#000080"/>
<circle cx="81.2" cy="144.6" r=".76" fill="none" stroke="#000080" stroke-width=".21"/>
<use href="#words"/>
</svg>
